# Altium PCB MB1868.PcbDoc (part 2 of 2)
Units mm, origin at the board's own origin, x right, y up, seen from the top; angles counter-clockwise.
Board outline 59.55 x 30 mm, 2 copper layers (Top Layer, Bottom Layer), stack 1.499 mm thick; 74 components, 54 nets, 296 pads, 554 vias.

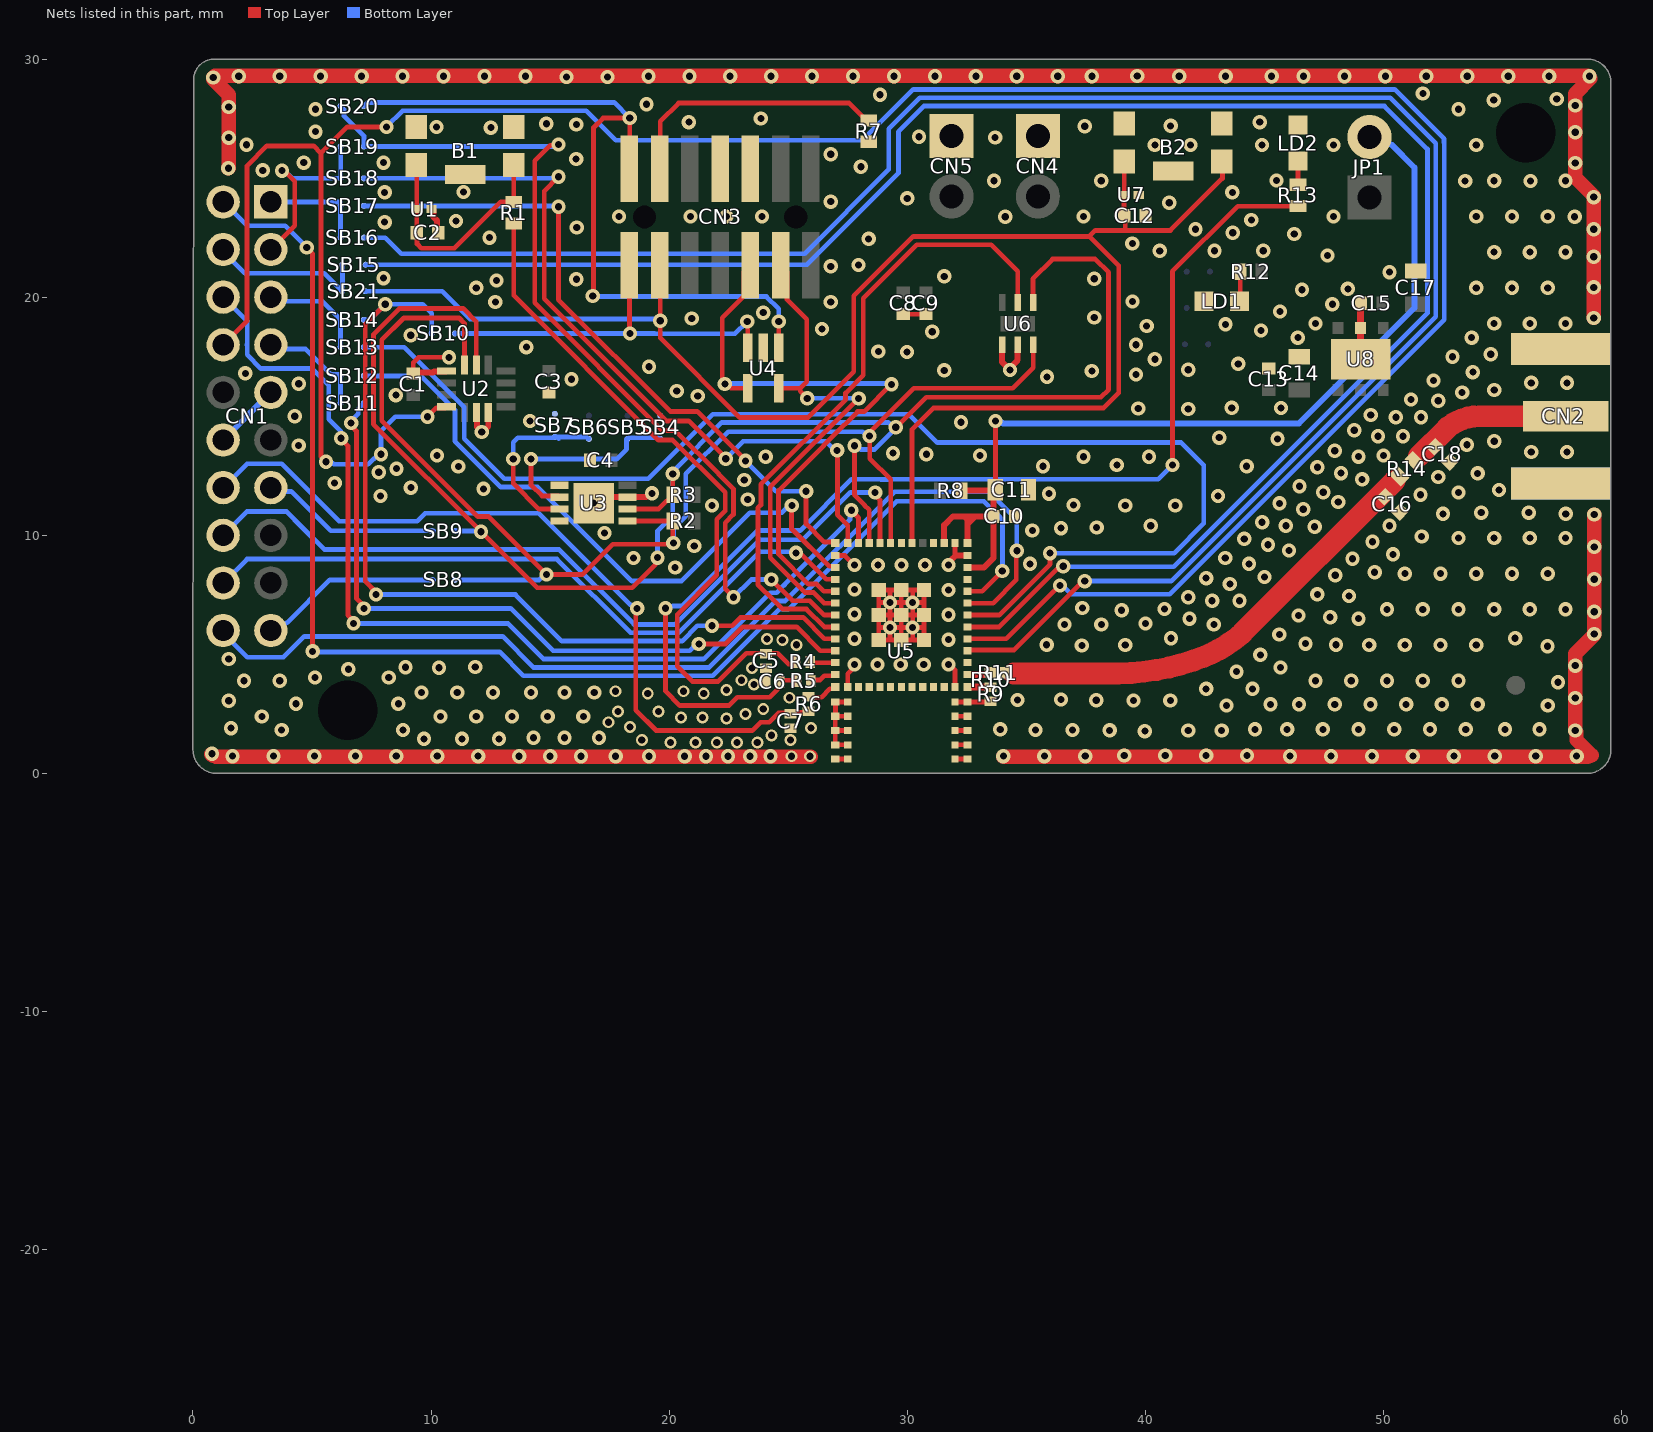
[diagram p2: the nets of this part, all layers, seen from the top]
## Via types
v1: diameter 0.6, hole 0.3, Top Layer to Bottom Layer, tented both sides, 522 vias
v2: diameter 0.5, hole 0.3, Top Layer to Bottom Layer, tented both sides, 32 vias

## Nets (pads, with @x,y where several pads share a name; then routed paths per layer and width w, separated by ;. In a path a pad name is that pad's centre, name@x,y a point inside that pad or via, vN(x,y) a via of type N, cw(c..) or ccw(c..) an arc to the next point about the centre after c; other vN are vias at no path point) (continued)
GND: B1.2 B1.4 B1.5 B2.2 B2.4 B2.5 C1.1 C2.1 C3.1 C4.1 C5.1 C6.1 C7.1 C8.1 C9.1 C10.1 C11.1 C12.1 C13.1 C14.1 C15.1 C16.2 C17.1 C18.2 CN1.5 CN1.16 CN2.2 CN2.3 CN2.4 CN2.5 CN3.5 CN3.7 CN4.1 CN5.1 LD1.2 LD2.2 R7.1 R9.2 SB4.1 SB7.2 U1.2 U2.1 U2.6 U2.7 U3.1 U3.4 U3.7 U3.EP U4.2 U5.1 U5.2 U5.3 U5.4 U5.5 U5.8 U5.15 U5.17 U5.19 U5.21 U5.24 U5.31 U5.43 U5.44 U5.45 U5.46 U5.47 U5.48 U5.49 U5.50 U5.51 U5.52 U5.53 U5.54 U5.55 U5.56 U5.57 U5.58 U5.59 U5.60 U5.61 U5.62 U5.63 U5.64 U5.65 U5.66 U5.67 U5.68 U5.69 U5.70 U5.71 U5.72 U5.73 U5.74 U5.75 U5.76 U5.77 U6.4 U6.5 U7.2 U8.2 U8.EP | length 182.7
  Top Layer w0.2: CN1.16@1.27,13.814 CN1.16@1.27,14 ; C1.1@9.255,16.845 9.255,17.255 9.473,17.473 v1(10.752,17.473) ; v1@19.192,11.76 v1(19.273,11.76) ; U5.46@26.964,1.199 U5.49@27.489,1.199 ; U5.46@26.975,1.2 U5.45@26.975,1.8 ; U5.44@26.975,2.4 26.975,1.814 26.989,1.799 U5.50@27.514,1.799 ; U5.43@26.975,3 26.989,2.986 26.989,2.399 U5.51@27.514,2.399 ; U5.31@26.975,9.15 27.382,9.15 v1(27.782,8.75) ; U5.43@26.981,2.995 U5.52@27.506,2.995 ; U5.47@26.989,0.599 U5.48@27.514,0.599 ; U5.53@27.498,3.631 27.498,4.183 27.782,4.467 v1(27.782,4.575) ; 28.8,6.125 v1@29.275,6.125 ; 28.8,7.175 v1@29.275,7.175 ; 29.275,5.6 v1@29.275,6.125 ; 29.275,7.7 v1@29.275,7.175 ; C8.1@29.834,19.287 C9.1@30.784,19.287 ; 30.225,5.6 v1@30.225,6.125 ; 30.225,7.7 v1@30.225,7.175 ; 30.7,6.125 v1@30.225,6.125 ; 30.7,7.175 v1@30.225,7.175 ; v1(31.726,4.575) 31.783,4.575 32.001,4.357 U5.63@32.001,3.614 ; U5.68@31.989,0.599 U5.1@32.514,0.599 ; U5.67@31.989,1.199 U5.2@32.514,1.199 ; U5.65@31.989,2.399 U5.4@32.514,2.399 ; 32,9.125 32,9.25 ; U5.19@32,9.675 32,9.25 ; U5.66@32.014,1.799 U5.3@32.539,1.799 ; U5.64@32.014,2.999 R9.2@33.3,2.999 ; 32.1,9.15 32,9.25 ; C15.1@49.034,19.722 C15.1@49.059,19.747 ; U5.76@28.8,6.65 U5.77@28.8,7.7 U5.72@29.75,7.7 ; U5.76@28.8,6.65 U5.73@29.75,6.65 ; U5.76@28.8,6.65 U5.75@28.8,5.6 U5.74@29.75,5.6 ; v1@29.275,6.125 v1@30.225,6.125 ; v1@29.275,6.125 v1@29.275,7.175 ; v1@29.275,7.175 v1@30.225,7.175 ; U5.74@29.75,5.6 U5.69@30.7,5.6 U5.70@30.7,6.65 ; U5.74@29.75,5.6 U5.73@29.75,6.65 ; U5.73@29.75,6.65 U5.70@30.7,6.65 ; U5.73@29.75,6.65 U5.72@29.75,7.7 ; U5.72@29.75,7.7 U5.71@30.7,7.7 U5.70@30.7,6.65 ; v1@30.225,6.125 v1@30.225,7.175
  Top Layer w0.25: C1.1@9.255,16.845 10.085,16.845 10.115,16.875 10.252,16.875 10.625,16.875 U2.1@10.65,16.9 ; U1.2@10.025,23.7 10.058,23.7 10.098,23.66 10.098,23.365 10.254,23.209 10.254,22.746 C2.1@10.3,22.7 ; U2.6@11.9,15.15 11.925,15.125 11.925,14.545 v1(12.129,14.341) 12.172,14.341 12.4,14.57 U2.7@12.4,15.15 ; v1(16.825,11.35) 17.075,11.6 U3.7@18.25,11.6 19.032,11.6 v1@19.192,11.76 ; v1@31.875,9 32,9.125 ; 32.1,9.15 U5.17@32.525,9.15 ; U6.4@33.984,17.662 33.984,17.272 34.311,16.945 v1(34.311,16.94) 34.311,17.035 34.634,17.358 U6.5@34.634,17.712
  Top Layer w0.3: U8.EP@49.034,17.547 U8.2@49.034,18.697 C15.1@49.034,19.722
  Top Layer w0.6: v1@0.767,0.809 0.809,0.767 0.858,0.734 0.912,0.712 0.97,0.7 1.659,0.7 10.258,0.7 v1@15,0.7 ; v1(1.486,25.411) 1.5,25.425 v1(1.5,26.7) v1(1.5,27.989) 1.5,28.5 0.85,29.15 v1(0.85,29.225) 0.925,29.3 1.899,29.3 v1(1.924,29.275) 1.949,29.3 3.619,29.3 v1(3.644,29.275) 3.669,29.3 5.338,29.3 v1(5.363,29.275) 5.388,29.3 7.058,29.3 v1(7.083,29.275) 7.108,29.3 8.778,29.3 v1(8.803,29.275) 8.828,29.3 10.497,29.3 v1(10.523,29.275) 10.548,29.3 12.217,29.3 v1(12.242,29.275) 12.267,29.3 13.937,29.3 v1(13.962,29.275) 13.987,29.3 15.641,29.3 v1(15.691,29.25) 15.741,29.3 17.361,29.3 v1(17.411,29.25) 17.461,29.3 19.08,29.3 19.13,29.25 19.18,29.3 20.8,29.3 v1@20.85,29.25 ; v1@15.05,0.7 v1@16.2,0.7 ; v1@16.4,0.7 v1@17.7,0.7 ; v1@17.8,0.7 v1@21.542,0.7 ; v1(20.85,29.275) 20.875,29.3 22.536,29.3 v1(22.561,29.275) 22.586,29.3 24.255,29.3 v1(24.28,29.275) 24.305,29.3 25.975,29.3 v1(26,29.275) 26.025,29.3 27.695,29.3 v1(27.72,29.275) 27.745,29.3 29.414,29.3 v1(29.439,29.275) ; v1@21.774,0.7 22.469,0.7 23.4,0.7 24.25,0.7 v2@25.95,0.7 ; v1@29.435,29.3 29.439,29.3 29.764,29.3 v1@34.599,29.3 ; v1@34.034,0.7 v1@37.474,0.7 ; v1(34.599,29.275) 34.624,29.3 36.293,29.3 v1(36.318,29.275) 36.343,29.3 37.725,29.3 v1(37.75,29.275) 37.775,29.3 39.643,29.3 v1(39.655,29.288) 39.666,29.3 41.401,29.3 v1(41.421,29.28) 41.441,29.3 43.333,29.3 43.369,29.264 43.406,29.3 45.275,29.3 v1@45.3,29.275 ; v1(37.474,0.725) 37.499,0.7 39.061,0.7 v1(39.111,0.75) 39.161,0.7 40.78,0.7 v1(40.83,0.75) 40.88,0.7 42.5,0.7 v1(42.55,0.75) 42.6,0.7 44.22,0.7 v1(44.27,0.75) 44.32,0.7 46.072,0.7 v1@51.231,0.7 ; v1@45.289,29.264 45.325,29.3 46.612,29.3 46.637,29.275 46.662,29.3 48.331,29.3 v1(48.356,29.275) 48.381,29.3 50.051,29.3 v1(50.076,29.275) 50.101,29.3 51.771,29.3 v1(51.796,29.275) 51.821,29.3 53.491,29.3 v1(53.516,29.275) 53.541,29.3 55.21,29.3 v1(55.235,29.275) 55.26,29.3 56.93,29.3 v1(56.955,29.275) 56.98,29.3 58.58,29.3 58.636,29.289 v1(58.65,29.275) ; v1(51.231,0.725) 51.256,0.7 52.926,0.7 v1(52.951,0.725) ; v1@52.951,0.7 58.58,0.7 58.638,0.712 58.692,0.734 58.741,0.767 ; 58.692,0.814 58.1,1.406 58.1,1.738 58.036,1.803 58.05,1.817 v1(58.05,3.164) v1(58.05,4.525) 58.05,5.025 58.85,5.825 v1(58.85,10.874) ; v1@58.692,29.186 58.05,28.544 v1(58.05,28.049) v1(58.05,26.925) v1(58.05,25.636) 58.05,25.026 58.825,24.251 v1(58.825,24.2) v1(58.825,22.85) v1(58.825,21.7) v1(58.825,20.411) 58.825,19.132 v1@58.836,19.122
  Bottom Layer w0.25: CN1.16@1.27,14 CN1.5@3.27,16
  other v1: 1.659,0.725 3.379,0.725 5.099,0.725 6.819,0.725 8.538,0.725 10.258,0.725 11.978,0.725 13.698,0.722 15,0.722 16.3,0.722 17.75,0.722 19.15,0.722 20.65,0.722 21.542,0.722 22.469,0.722 23.4,0.722 24.25,0.722 34.034,0.725 35.754,0.725 46.072,0.725 47.792,0.725 49.512,0.725 54.671,0.725 56.39,0.725 58.11,0.725 0.8,0.825 9.7,1.45 11.3,1.45 12.85,1.45 14.3,1.5 15.6,1.5 17.05,1.5 39.975,1.775 38.495,1.808 41.8,1.8 43.2,1.8 58.05,1.803 3.725,1.825 8.825,1.825 35.385,1.825 36.935,1.825 33.9,1.85 44.6,1.85 45.95,1.85 47.45,1.85 48.95,1.85 50.45,1.85 51.95,1.85 53.45,1.85 55.1,1.85 56.55,1.85 1.6,1.9 2.895,2.39 10.395,2.39 11.895,2.39 13.395,2.39 14.895,2.39 16.395,2.39 43.4,2.85 56.9,2.85 45.25,2.9 46.45,2.9 47.95,2.9 49.45,2.9 50.95,2.9 52.45,2.9 53.95,2.9 4.325,2.925 8.625,2.925 1.5,3.05 39.495,3.058 41.045,3.058 34.631,3.083 37.935,3.075 36.456,3.108 9.6,3.4 11.1,3.4 12.6,3.4 14.2,3.4 15.6,3.4 16.85,3.4 42.55,3.55 44.5,3.55 57.325,3.825 2.145,3.89 3.645,3.89 47.145,3.89 48.645,3.89 50.145,3.89 51.645,3.89 53.145,3.89 5.125,4.025 8.225,4.025 43.826,4.274 6.525,4.375 8.926,4.456 10.337,4.437 45.676,4.449 11.856,4.472 28.75,4.575 29.719,4.575 30.688,4.575 1.5,4.8 44.826,4.979 56.881,5.342 37.33,5.367 35.85,5.4 39.155,5.392 48,5.4 49.395,5.39 50.895,5.39 52.395,5.39 53.895,5.39 46.726,5.449 31.726,5.619 27.782,5.656 41.075,5.675 55.525,5.675 45.626,5.829 58.85,5.85 29.269,6.127 30.219,6.127 36.6,6.25 38.15,6.25 42.875,6.25 40.005,6.292 41.85,6.5 48.95,6.5 47.757,6.559 46.426,6.629 31.726,6.662 27.782,6.687 58.85,6.791 39,6.85 40.8,6.9 50.145,6.89 51.645,6.89 53.145,6.89 54.645,6.89 56.145,6.89 57.645,6.89 37.35,6.95 29.269,7.177 30.219,7.177 42.8,7.25 43.95,7.25 41.8,7.4 48.55,7.45 47.219,7.52 31.726,7.706 27.782,7.719 43.546,7.951 58.85,8.152 42.55,8.2 45,8.25 47.969,8.32 50.895,8.39 52.395,8.39 53.895,8.39 55.395,8.39 56.895,8.39 49.625,8.45 20.25,8.65 28.768,8.75 29.754,8.75 30.74,8.75 31.726,8.75 35.15,8.8 44.346,8.801 48.698,9.012 18.5,9.05 43.35,9.05 50.4,9.2 46.03,9.36 58.85,9.513 21.05,9.55 45.146,9.601 49.539,9.728 44.15,9.85 53.145,9.89 54.645,9.89 56.145,9.89 57.645,9.89 51.6,9.95 17.279,10.1 35.25,10.2 36.45,10.3 37.95,10.325 47.105,10.36 40.225,10.4 45.896,10.401 50.25,10.4 44.9,10.55 52.5,10.9 57.65,10.9 54.1,10.95 56.1,10.95 46.626,11.093 21.8,11.25 39.15,11.25 41.25,11.25 36.975,11.275 45.63,11.342 48.1,11.4 23.3,11.5 7.872,11.651 43.05,11.65 51.55,11.7 35.95,11.75 53.15,11.8 47.466,11.809 54.85,11.9 12.2,11.95 9.15,12 46.47,12.058 5.95,12.2 23.15,12.323 49.1,12.35 52.3,12.45 48.216,12.609 53.95,12.6 7.8,12.65 8.55,12.8 47.22,12.858 11.145,12.89 35.7,12.9 44.25,12.9 38.8,12.95 24.05,13.3 37.4,13.3 40.15,13.3 48.946,13.301 10.25,13.35 33.05,13.35 50,13.35 30.8,13.4 29.4,13.45 56.2,13.5 57.7,13.5 47.95,13.55 4.439,13.771 53.5,13.8 54.65,13.95 45.55,14.05 43.1,14.1 49.766,14.159 50.82,14.158 48.77,14.408 32.251,14.745 14.15,14.8 50.516,14.959 51.57,14.958 4.275,15 49.461,15.055 41.8,15.3 39.7,15.325 43.625,15.35 45.691,15.342 52.3,15.65 51.15,15.7 21.2,15.85 8.52,15.885 53.3,16 20.316,16.055 54.65,16.1 4.445,16.363 56.2,16.4 57.7,16.4 52.1,16.5 15.9,16.55 35.87,16.654 39.6,16.75 2.2,16.8 53.75,16.85 37.75,16.9 31.55,16.925 41.8,16.95 19.15,17.075 43.9,17.2 40.395,17.39 52.9,17.5 54.5,17.6 28.783,17.716 29.988,17.695 14,17.9 39.6,18 46.4,18.3 53.7,18.3 9.146,18.401 31.05,18.55 44.85,18.6 26.42,18.661 40.052,18.791 43.361,18.858 47.145,18.89 54.645,18.89 56.145,18.89 57.645,18.89 20.95,19.1 58.825,19.122 37.85,19.15 23.95,19.35 45.65,19.4 47.85,19.7 12.7,19.8 26.785,19.793 39.453,19.821 46.572,20.314 48.5,20.35 11.895,20.39 53.895,20.39 55.395,20.39 56.895,20.39 12.75,20.7 16.1,20.75 37.85,20.775 8,20.8 31.55,20.875 50.25,21.05 26.785,21.294 27.95,21.35 47.65,21.75 54.645,21.89 56.145,21.89 57.645,21.89 40.599,21.944 42.9,21.95 44.95,21.95 39.45,22.25 28.375,22.45 12.45,22.5 46.25,22.65 43.666,22.705 42.1,22.85 16.116,22.93 8.05,23.15 11.05,23.2 44.448,23.244 34.114,23.377 58.025,23.375 17.895,23.39 20.895,23.39 22.395,23.39 23.895,23.39 37.395,23.39 47.895,23.39 53.895,23.39 55.395,23.39 56.895,23.39 41,23.962 26.785,24.011 30,24.15 8.05,24.4 43.65,24.4 11.361,24.414 53.425,24.875 56.175,24.875 33.645,24.89 38.145,24.89 45.5,24.9 54.645,24.89 57.645,24.89 2.928,25.325 28.05,25.475 4.65,25.65 8,25.65 16.091,25.805 26.785,26.005 2.25,26.4 40.395,26.39 41.895,26.39 44.895,26.39 47.895,26.39 53.895,26.39 33.689,26.702 30.489,26.739 5.15,26.95 12.51,27.119 10.224,27.15 37.45,27.175 41.059,27.194 16.1,27.25 14.841,27.28 20.825,27.35 44.804,27.349 23.85,27.5 5.145,27.89 53.145,27.89 19.05,28.1 54.625,28.275 57.275,28.325 28.85,28.5 51.65,28.55 19.13,29.275 31.159,29.275 32.879,29.275 43.369,29.28 45.3,29.28 46.637,29.28
  other v2: 25.129,0.722 25.911,0.722 20.05,1.301 21.1,1.3 22,1.3 22.85,1.3 23.7,1.3 18.85,1.4 25.1,1.4 24.3,1.6 25.95,1.9 18.35,1.95 17.45,2.15 22.4,2.3 20.5,2.35 21.4,2.35 23.2,2.5 17.85,2.6 19.55,2.6 23.95,2.7 25.055,3.178 19.1,3.35 21.45,3.35 17.75,3.45 20.6,3.45 22.4,3.5 23.56,3.728 23.034,3.913 23.473,4.429 25.35,5.4 24.75,5.6 24.1,5.65
GNDDetect: CN3.11 R7.2 | length 10.4
  Top Layer w0.2: CN3.11@19.625,26.325 19.625,27.379 20.396,28.15 27.555,28.15 28.125,27.58 28.28,27.425 R7.2@28.375,27.425
I2C1_SCL: R3.2 SB9.1 U2.13 U3.6 U5.27 U6.1 | length 70.2
  Top Layer w0.2: U2.13@11.9,17.15 11.9,18.975 11.35,19.525 8.678,19.525 7.581,18.428 7.581,14.669 v1(12.1,10.15) 14.45,7.8 18.45,7.8 19.436,8.786 19.436,8.983 v1(19.512,9.06) ; U3.6@18.25,11.1 19.55,11.1 19.9,11.45 19.995,11.45 20.15,11.605 R3.2@20.15,11.7 v1(20.15,12.58) v1@20.15,12.68 ; v1(27.779,13.759) 27.779,11.698 28.2,11.278 28.2,11.271 28.4,11.071 U5.27@28.4,9.675 ; v1@29.5,14.5 30.8,15.8 38.133,15.8 38.45,16.117 38.45,21.038 37.888,21.6 36.1,21.6 35.274,20.774 U6.1@35.274,19.777
  Bottom Layer w0.2: SB9.1@11,10.175 11.05,10.175 12.075,10.175 v1(12.1,10.15) ; v1(19.512,9.06) 19.512,10.187 20.15,10.825 v1@20.15,12.537 ; v1@20.169,12.68 20.289,12.8 20.289,12.818 22.208,14.738 29.204,14.738 29.404,14.538 v1(29.513,14.538) ; v1(27.779,13.759) 27.888,13.759 28.047,13.6 28.617,13.6 v1@29.533,14.517
I2C1_SDA: R2.2 SB8.1 U2.14 U3.5 U5.25 U6.6 | length 56.8
  Top Layer w0.2: U2.14@11.4,17.15 11.4,18.909 11.184,19.125 8.85,19.125 7.931,18.206 7.931,14.814 11.957,10.787 12.413,10.787 v1(14.85,8.35) 16.351,8.35 17.626,9.625 19.969,9.625 20.044,9.7 v1@20.125,9.7 ; U3.5@18.25,10.6 R2.2@20.15,10.6 v1@20.15,9.7 ; v1@28.364,14.267 30.272,16.175 34.427,16.175 35.284,17.032 U6.6@35.284,17.997 ; v1@28.41,14.271 v1(28.41,14.171) 28.422,14.158 28.422,13.222 29.3,12.344 U5.25@29.3,9.675
  Bottom Layer w0.2: 11.225,8.125 14.533,8.125 14.758,8.35 v1(14.85,8.35) ; v1(20.175,9.675) 20.175,10.285 20.7,10.809 20.7,12.575 22.475,14.35 28.122,14.35 28.427,14.046 v1@28.472,14.046
NetB1_1: B1.1 B1.3 C2.2 R1.1 U1.1 | length 9.8
  Top Layer w0.2: B1.1@9.375,25.55 9.4,25.525 U1.1@9.4,23.7 C2.2@9.4,22.7 9.413,22.687 9.413,22.237 9.594,22.056 10.981,22.056 12.925,24 R1.1@13.475,24 B1.3@13.475,25.55
NetC6_1: C18.1 CN2.1 R14.2 | length 6.8
  Top Layer w0.914: 51.483,13.317 52.688,14.523 cw(c54.043,12.838) 54.016,15 54.022,15 56.3,15 CN2.1@57.65,15
NetC7_1: C16.1 R11.1 R14.1 | length 19
  Top Layer w0.914: 34.475,4.2 38.849,4.2 38.853,4.2 ccw(c38.756,14.276) 42.024,4.744 ccw(c40.331,10.156) 44.051,5.877 50.462,12.288
NetCN1_1: CN1.1 SB16.2 SB17.2 | length 4.3
  Bottom Layer w0.2: CN1.1@3.275,24.005 CN1.1@3.27,24 6.2,24 ; SB16.2@6.2,22.5 SB17.2@6.2,23.833
NetCN1_2: CN1.2 SB18.2 SB19.2 | length 7.9
  Top Layer w0.2: CN1.2@3.27,22 4.275,23.005 4.275,24.864 3.825,25.314 v1(3.735,25.314)
  Bottom Layer w0.2: v1(3.735,25.314) 3.843,25.314 4.165,24.992 6.206,24.992 SB19.2@6.206,26.325
NetCN1_3: CN1.3 SB13.2 SB14.2 | length 4.5
  Bottom Layer w0.2: CN1.3@3.27,20 3.445,19.825 5.425,19.825 SB14.2@6.2,19.05 SB13.2@6.2,17.9
NetCN1_4: CN1.4 SB11.2 SB12.2 | length 4.6
  Bottom Layer w0.2: CN1.4@3.27,18 3.45,17.82 4.73,17.82 5.8,16.75 6.17,16.75 SB12.2@6.22,16.7 ; SB11.2@6.2,15.55 SB12.2@6.2,16.7
NetCN1_7: CN1.7 SB9.2 | length 7.6
  Bottom Layer w0.2: CN1.7@3.27,12 3.427,11.843 4.127,11.843 5.783,10.188 SB9.2@10.112,10.188
NetCN1_10: CN1.10 SB8.2 | length 7.7
  Bottom Layer w0.2: CN1.10@3.27,6 3.595,6 3.924,6.33 3.955,6.33 5.75,8.125 10.045,8.125 SB8.2@10.1,8.125
NetCN1_12: CN1.12 SB15.1 SB21.1 | length 6.9
  Bottom Layer w0.2: CN1.12@1.27,22 1.27,21.905 2.175,21 2.856,21 5.504,21 SB21.1@6.265,20.239 ; SB21.1@6.275,20.229 SB21.1@6.265,20.239 ; SB15.1@6.275,21.362 6.275,20.25 SB21.1@6.265,20.239
NetLD1_1: LD2.1 R13.2 | length 1
  Top Layer w0.2: R13.2@46.406,24.722 46.409,24.725 LD2.1@46.409,25.722
NetLD2_1: LD1.1 R12.2 | length 1.3
  Top Layer w0.2: LD1.1@43.959,19.828 43.98,19.849 R12.2@43.98,21.072
NetR1_1: R9.1 R10.2 U5.6 | length 0.8
  Top Layer w0.3: U5.6@32.525,3.625 R9.1@33.325,3.625
NetR2_1: R10.1 R11.2 U5.7 | length 1
  Top Layer w0.3: U5.7@32.55,4.15 R11.2@33.5,4.15
NetSB13_2: SB4.2 SB5.2 U3.2 | length 8.6
  Top Layer w0.2: v1(14.2,13.2) 14.2,12.111 14.661,11.65 15.35,11.65 U3.2@15.4,11.6
  Bottom Layer w0.2: v1(14.2,13.2) 17.8,13.2 18.212,13.612 18.212,14.032 SB5.2@18.25,14.07 ; SB5.2@18.265,14.05 18.315,14.1 19.55,14.1 19.6,14.05 SB4.2@19.625,14.05
NetSB15_2: SB6.2 SB7.1 U3.3 | length 7.5
  Top Layer w0.2: v1(13.45,13.2) 13.45,12.175 14.525,11.1 U3.3@15.4,11.1
  Bottom Layer w0.2: v1(13.45,13.2) 13.45,13.9 13.65,14.1 15.137,14.1 15.151,14.115 15.19,14.115 SB7.1@15.2,14.125 SB7.1@15.285,14.125 ; 15.36,14.05 SB7.1@15.285,14.125 ; SB6.2@16.625,14.05 16.61,14.05 16.535,14.125 SB7.1@15.285,14.125
NRST: B2.1 B2.3 C12.2 CN3.12 SB21.2 U5.23 U7.1 | length 71.9
  Top Layer w0.2: CN3.12@19.6,21.336 19.624,21.312 v1(19.624,19.012) 19.624,18.289 22.972,14.941 25.827,14.941 27.75,16.864 27.75,20.05 30.25,22.55 37.65,22.55 ; U5.23@30.2,9.675 30.2,14.45 31.1,15.35 38.249,15.35 38.875,15.976 38.875,21.325 37.65,22.55 ; C12.2@39.097,23.418 U7.1@39.097,24.293 ; C12.2@39.109,23.418 39.15,23.378 39.15,22.804 ; U7.1@39.109,24.431 B2.1@39.109,25.697 B2.1@39.109,25.856 ; B2.3@43.234,25.831 43.234,24.984 41.05,22.8 37.9,22.8 37.65,22.55
  Bottom Layer w0.2: SB21.2@7.25,20.25 7.261,20.239 7.275,20.239 7.286,20.25 10.466,20.25 11.629,19.087 v1@19.624,19.087
PA0: U5.37 U6.2 | length 27
  Top Layer w0.2: U5.37@26.975,6.15 26.515,6.15 25.765,6.9 24.767,6.9 24.076,7.591 24.063,7.591 23.724,7.931 23.724,11.146 23.85,11.272 23.85,12.137 27.407,15.695 27.407,15.974 28.15,16.717 28.15,19.955 30.395,22.2 33.525,22.2 34.634,21.091 U6.2@34.634,19.777
PA1: SB15.2 U5.11 | length 80.8
  Top Layer w0.2: U5.11@32.525,6.15 33.855,6.15 v1@36.395,8.69 ; v1@36.473,8.623 v1(36.55,8.7)
  Bottom Layer w0.2: SB15.2@7.25,21.362 25.787,21.362 29.625,25.2 29.625,26.95 30.7,28.025 50.035,28.025 51.842,26.217 51.842,19.332 41.185,8.675 36.575,8.675 v1(36.55,8.7)
PA2: CN1.20 U5.13 | length 43.3
  Top Layer w0.2: U5.13@32.525,7.15 33.6,7.15 34.575,8.125 34.575,9.083 34.593,9.1 v1@34.593,9.332
  Bottom Layer w0.2: CN1.20@1.27,6 1.27,5.88 2.275,4.875 3.8,4.875 4.675,5.75 5.722,5.75 13,5.75 14.3,4.45 21.678,4.45 24.469,7.241 24.871,7.241 29.405,11.775 29.409,11.775 29.459,11.825 33.43,11.825 34.6,10.655 v1@34.6,9.375
  other v1: 34.6,9.35
PA3: CN1.13 U5.28 | length 43.1
  Top Layer w0.2: v1(6.223,14.077) 6.223,14.046 6.51,13.759 6.51,6.641 6.742,6.408 v1(6.742,6.3) ; v1(27.65,11.05) 27.65,11.033 27.95,10.733 U5.28@27.95,9.675 U5.28@27.93,9.695
  Bottom Layer w0.2: CN1.13@1.27,20 2.216,19.054 2.275,18.995 2.275,18.1 ccw(c3.27,18) 2.275,17.9 2.275,17.581 2.856,17 5,17 5.7,16.3 5.7,14.872 6.223,14.349 v1(6.223,14.077) ; v1(6.742,6.3) 13.225,6.3 14.725,4.8 21.45,4.8 24.241,7.591 24.519,7.591 24.841,7.914 27.59,10.662 27.59,10.99 v1(27.65,11.05)
PA4: SB16.1 U5.9 | length 82.5
  Top Layer w0.2: U5.9@32.525,5.15 32.56,5.185 34.481,5.185 36.636,7.34 36.638,7.34 36.96,7.662 36.96,7.664 37.371,8.075 v1(37.451,8.075)
  Bottom Layer w0.2: SB16.1@7.225,22.5 8.075,22.5 8.747,21.828 25.687,21.828 29.225,25.366 29.225,27.075 30.525,28.375 50.275,28.375 52.192,26.458 52.192,19.187 41.08,8.075 v1(37.451,8.075)
PA5: SB11.1 U5.39 | length 30.4
  Top Layer w0.2: v1(6.643,14.714) 6.643,14.606 6.781,14.467 6.781,14.46 6.864,14.378 6.864,7.348 7.177,7.034 v1(7.177,6.926) ; v1(21.246,5.435) 22.377,5.435 23.092,6.15 25.35,6.15 26.35,5.15 U5.39@26.975,5.15
  Bottom Layer w0.2: v1(6.643,14.714) 6.643,14.802 6.937,15.096 6.937,15.298 7.175,15.535 SB11.1@7.175,15.55 ; v1(7.177,6.926) 13.349,6.926 15.125,5.15 20.853,5.15 21.138,5.435 v1(21.246,5.435)
PA6: SB13.1 U5.12 | length 54.6
  Top Layer w0.2: U5.12@32.525,6.65 33.86,6.65 35.993,8.783 v1(35.993,9.25)
  Bottom Layer w0.2: SB13.1@7.175,17.9 8.869,17.9 11.389,15.38 11.389,14.061 13.075,12.375 19.111,12.375 19.917,13.181 19.922,13.181 21.828,15.088 30.062,15.088 31.255,13.895 32.817,13.895 32.822,13.9 33.278,13.9 33.283,13.895 41.505,13.895 42.45,12.95 42.45,10.5 41.2,9.25 v1(35.993,9.25)
PA7: SB18.1 U5.29 | length 33.2
  Top Layer w0.2: v1(15.35,25.056) 14.75,24.456 14.75,19.931 19.881,14.8 20.825,14.8 22.375,13.25 v1(22.375,13.215) ; v1@27.064,13.556 27.064,10.858 27.5,10.422 U5.29@27.5,9.675
  Bottom Layer w0.2: SB18.1@7.175,24.992 7.225,24.992 15.206,24.992 15.269,25.056 v1(15.35,25.056) ; v1(22.375,13.215) 23.104,13.944 26.58,13.944 26.957,13.568 v1(27.053,13.568)
PA8: CN1.14 U2.4 U5.10 | length 114.9
  Top Layer w0.2: CN1.14@1.27,18 2.27,19 2.27,25.52 3.1,26.35 5.075,26.35 5.375,26.05 ; v1(5.591,13.087) 5.375,13.303 5.375,26.05 ; v1(8.125,27.15) 6.475,27.15 5.375,26.05 ; v1(9.85,14.975) 10.225,15.35 10.6,15.35 U2.4@10.65,15.4 ; U5.10@32.525,5.65 34.15,5.65 36.39,7.89 v1(36.41,7.89)
  Bottom Layer w0.2: v1(5.591,13.087) 5.667,13.011 5.877,13.011 5.908,12.98 7.352,12.98 7.572,13.2 7.592,13.2 7.792,13.4 v1(7.9,13.4) 7.9,14.381 8.494,14.975 v1(9.85,14.975) ; v1(8.125,27.15) 8.805,27.83 16.515,27.83 17.76,26.585 28.11,26.585 30.25,28.725 50.47,28.725 52.542,26.653 52.542,26.487 52.55,26.479 52.55,19.05 41.025,7.525 36.883,7.525 36.518,7.89 v1(36.41,7.89)
PA9-TX: SB10.2 SB14.1 U5.38 | length 37.7
  Top Layer w0.2: v1(7.684,7.51) 7.684,7.618 7.231,8.072 7.231,18.856 v1(8.075,19.7) ; v1(21.8,6.2) 22.647,6.2 22.997,6.55 25.62,6.55 26.52,5.65 U5.38@26.975,5.65
  Bottom Layer w0.2: SB14.1@7.175,19.05 7.425,19.05 v1(8.075,19.7) 9.65,19.7 10.025,19.325 SB10.2@10.025,18.475 ; v1(7.684,7.51) 13.54,7.51 15.494,5.556 20.539,5.556 21.183,6.2 v1(21.8,6.2)
PA10-RX: SB19.1 SB20.2 U5.36 | length 39
  Top Layer w0.2: v1(15.35,26.413) 15.317,26.38 15.005,26.38 14.35,25.725 14.35,19.766 19.716,14.4 20.25,14.4 22.095,12.555 22.095,12.55 22.7,11.945 22.7,10.877 22.35,10.527 22.35,7.75 v1(22.7,7.4) ; v1(24.291,8.141) 25.168,7.265 25.168,7.25 25.91,7.25 26.51,6.65 U5.36@26.975,6.65
  Bottom Layer w0.2: SB20.2@6.2,28.023 6.338,27.885 6.338,27.612 7.181,26.769 7.181,26.331 SB19.1@7.175,26.325 ; SB19.1@7.181,26.325 v1@15.181,26.325 ; v1(22.7,7.4) 23.441,8.141 v1(24.291,8.141)
PA11: SB12.1 U5.32 | length 27.1
  Top Layer w0.2: v1(25.15,11.25) 25.136,11.236 25.136,10.281 26.717,8.7 26.925,8.7 U5.32@26.975,8.65
  Bottom Layer w0.2: SB12.1@7.225,16.689 9.585,16.689 11,15.274 11,13.955 12.93,12.025 14.475,12.025 18.425,8.075 20.512,8.075 23.387,10.95 24.732,10.95 24.867,11.085 24.877,11.085 25.042,11.25 v1(25.15,11.25)
PA12: SB17.1 U5.30 | length 28.8
  Top Layer w0.2: v1(15.35,23.8) 15.35,19.897 20.047,15.2 21.175,15.2 23.2,13.175 v1(23.2,13.125) ; v1(25.75,11.85) 25.75,10.478 26.514,9.714 26.936,9.714 U5.30@26.975,9.675
  Bottom Layer w0.2: SB17.1@7.175,23.833 15.317,23.833 v1(15.35,23.8) ; v1(23.2,13.125) 24.475,11.85 v1(25.75,11.85)
PA13-SWDIO: CN3.4 U4.5 U5.35 | length 21.6
  Top Layer w0.2: CN3.4@24.68,21.336 24.95,21.066 24.95,19.9 25.775,19.075 25.775,16.45 25.5,16.175 ; U4.5@24.7,15.675 24.7,16.075 U4.5@24.6,16.175 25.5,16.175 ; v1(25.8,15.75) 25.5,16.05 25.5,16.175 ; U5.35@26.975,7.15 26.9,7.15 26.505,7.15 26.055,7.6 25.7,7.6 24.243,9.057 24.243,12.032 v1(27.957,15.746)
  Bottom Layer w0.2: v1(25.8,15.75) 27.954,15.75 v1(27.957,15.746)
PA14-SWCLK: CN3.6 U4.4 U5.34 | length 25.9
  Top Layer w0.2: v1@22.317,16.333 22.225,16.425 22.225,19.126 23.14,20.041 23.14,21.066 CN3.6@23.41,21.336 ; v1(22.337,16.353) 22.418,16.353 22.597,16.175 U4.4@23.3,16.175 ; U5.34@26.975,7.65 26.5,7.65 26.2,7.95 25.85,7.95 24.593,9.207 24.593,11.876 26.503,13.786 26.503,13.796 26.825,14.118 26.835,14.118 27.913,15.196 28.185,15.196 29.328,16.339 v1(29.339,16.339)
  Bottom Layer w0.2: v1@22.337,16.375 29.303,16.375 v1(29.339,16.339)
PB0: C6.2 R5.1 R13.1 | length 48.1
  Top Layer w0.2: v1(19.848,6.938) 19.848,3.446 20.443,2.85 22.508,2.85 22.858,3.2 24.215,3.2 24.55,3.535 24.55,3.739 C6.2@24.65,3.839 24.728,3.916 R5.1@25.366,3.916 ; v1(41.134,12.947) 41.134,21.084 43.872,23.822 R13.1@46.406,23.822
  Bottom Layer w0.2: v1(19.848,6.938) 19.924,7.015 20.151,7.015 20.165,7.029 20.527,7.029 23.698,10.2 25.505,10.2 27.655,12.35 28.878,12.35 28.884,12.344 29.3,12.344 29.306,12.35 40.537,12.35 v1(41.134,12.947)
PB0_S: R5.2 U5.41 | length 1.1
  Top Layer w0.2: R5.2@25.947,3.887 25.979,3.92 26.329,3.92 26.51,4.1 26.925,4.1 U5.41@26.975,4.15
PB1: C5.2 R1.2 R4.1 | length 29.4
  Top Layer w0.2: R1.2@13.475,23.1 13.475,20.075 19.55,14 20.15,14 22.35,11.8 22.35,11.022 22,10.672 22,8.332 20.34,6.672 20.34,4.498 20.979,3.858 22.045,3.858 23.237,5.05 23.85,5.05 24.55,5.05 25.013,4.587 R4.1@25.313,4.587
PB1_S: R4.2 U5.40 | length 1.1
  Top Layer w0.2: R4.2@25.916,4.686 25.951,4.65 U5.40@26.975,4.65
PB2: C7.2 CN1.17 R6.1 | length 32.8
  Top Layer w0.2: v1(18.654,6.93) 18.6,6.875 18.6,2.65 19.449,1.801 21.344,1.801 21.346,1.8 23.485,1.8 23.835,2.15 24.196,2.15 24.596,2.55 C7.2@25.05,2.55 ; C7.2@25.059,2.559 25.798,2.559 R6.1@25.853,2.614
  Bottom Layer w0.2: CN1.17@1.27,12 2.27,13 3.725,13 6.138,10.588 9.409,10.588 9.747,10.925 14.514,10.925 18.357,7.081 18.395,7.081 18.546,6.93 v1(18.654,6.93)
PB2_S: R6.2 U5.42 | length 1.2
  Top Layer w0.2: R6.2@25.95,3.2 26.4,3.2 26.75,3.55 26.9,3.55 U5.42@26.975,3.625
PB4: CN1.19 U5.33 | length 29.3
  Top Layer w0.2: v1(25.321,9.263) 25.398,9.186 25.569,9.186 26.605,8.15 U5.33@26.975,8.15
  Bottom Layer w0.2: CN1.19@1.27,8 2.27,9 15.284,9 18.378,5.906 20.394,5.906 23.796,9.308 25.276,9.308 v1(25.321,9.263)
PB5: CN1.18 U5.26 | length 34.3
  Top Layer w0.2: v1(28.65,11.8) 28.65,11.692 28.85,11.492 28.85,9.75 U5.26@28.85,9.675
  Bottom Layer w0.2: CN1.18@1.27,10 2.27,11 3.925,11 4.6,10.325 5.525,9.4 15.379,9.4 18.523,6.256 20.249,6.256 23.809,9.816 25.616,9.816 27.6,11.8 v1(28.65,11.8)
PB8: CN1.11 U5.14 | length 58.1
  Top Layer w0.2: v1(4.777,22.089) 4.777,22.07 5.025,21.822 v1(5.025,5.125) ; U5.14@32.525,7.65 33.14,7.65 v1(33.987,8.497)
  Bottom Layer w0.2: CN1.11@1.27,24 2.27,23 3.867,23 v1(4.777,22.089) ; v1(5.025,5.125) 5.05,5.1 12.875,5.1 13.875,4.1 21.823,4.1 21.948,4.225 24.614,6.891 25.016,6.891 29.55,11.425 33.218,11.425 34,10.643 34,8.51 v1(33.987,8.497)
VCP_RX: CN3.13 SB20.1 U4.1 | length 31.2
  Top Layer w0.2: v1(16.792,20.048) 16.825,20.081 16.825,27.125 17.22,27.52 v1(18.345,27.52) 18.341,27.516 CN3.13@18.341,26.339 ; CN3.13@18.316,25.514 CN3.13@18.33,25.5 ; U4.1@24.6,17.875 v1(24.6,18.975)
  Bottom Layer w0.2: SB20.1@7.175,28.023 7.332,28.18 17.686,28.18 v1(18.345,27.52) ; v1@16.792,19.948 v1@16.849,20.005 ; v1@16.792,20.025 24.083,20.025 24.6,19.508 v1(24.6,18.975)
VCP_TX: CN3.14 SB10.1 U4.3 | length 16.6
  Top Layer w0.2: CN3.14@18.33,21.336 18.33,18.403 v1@18.358,18.375 ; v1(23.275,18.975) 23.3,18.95 U4.3@23.3,17.875
  Bottom Layer w0.2: SB10.1@11,18.475 v1(18.358,18.475) 19.383,18.475 19.396,18.462 22.762,18.462 v1(23.275,18.975)
VDD: C10.2 C11.2 JP1.2 R8.1 U5.16 U5.18 U5.20 | length 41
  Top Layer w0.2: C11.2@33.69,11.915 33.7,11.925 v1(33.7,14.8)
  Top Layer w0.25: U5.20@31.55,9.675 31.55,10.225 31.55,10.425 31.915,10.79 32.39,10.79 ; R8.1@32.275,11.875 33.65,11.875 33.615,11.84 C10.2@33.615,10.79 ; U5.16@32.525,8.65 33.225,8.65 33.625,9.05 33.625,10.78 C10.2@33.615,10.79 ; U5.18@32.525,9.675 32.525,10.45 ; 32.39,10.79 32.865,10.79 ; 32.39,10.79 32.525,10.655 32.525,10.45 ; 32.525,10.45 32.865,10.79 ; 32.865,10.79 C10.2@33.615,10.79
  Bottom Layer w0.25: v1(33.7,14.8) 33.767,14.733 33.977,14.733 34.01,14.7 46.45,14.7 51.3,19.55 51.3,25.438 50.317,26.421 49.715,26.421 JP1.2@49.409,26.727
pads on no net: 1.1 CN1.8 CN1.9 CN3.0 CN3.1 CN3.2 CN3.8 CN3.9 CN3.10 Designator1.1 Designator2.1 U2.9 U2.10 U6.7 U8.3 U8.5

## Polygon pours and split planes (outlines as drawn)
GND on Top Layer "GND_L01_P000" (solid, remove dead copper, pour order 0): -1.47,29.572 -1.47,-0.928 58.605,-0.928 59.33,-0.203 59.33,28.847 58.605,29.572
GND on Bottom Layer "GND_L02_P001" (solid, remove dead copper, pour order 1): 0.225,31.025 -0.75,30.05 -0.75,0.55 0.75,-0.95 58.875,-0.95 60.725,0.9 60.725,29.775 59.475,31.025

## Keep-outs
Keep-Out Layer:
  region: 58.4,25.1 59.55,23.95 59.55,29.55 58.4,28.4
  region: 1.15,25.1 0,23.95 0,29.55 1.15,28.4
  region: 1.15,1.6 0,0.45 0,6.05 1.15,4.9
  region: 58.4,1.6 59.55,0.45 59.55,6.05 58.4,4.9

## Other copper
Top Layer:
  pour cut-out: 33.226,20.348 32.884,20.007 32.884,17.613 33.146,17.352 36.024,17.352 36.337,17.716 36.337,19.082 36.331,19.708 36.331,19.988 36.306,20.014 36.276,20.043 36.201,20.119 36.133,20.215 36.106,20.279 36.095,20.313 36.087,20.348
  text "1" at 2.25,27 h2
Bottom Layer:
  pour cut-out: 36.124,20.222 36.088,20.337 33.218,20.341 32.884,20.007 32.884,17.613 33.146,17.352 36.024,17.352 36.333,17.712 36.333,18.348 36.327,18.673 36.337,18.843 36.333,18.983 36.333,19.103 36.327,19.468 36.333,19.981 36.274,20.041 36.188,20.134
  text "2" at 4.5,27 h2
Multi-Layer:
  pour cut-out: 31.75,0.2 31.75,3.2 27.75,3.2 27.75,0.2
  pour cut-out: 2,28.5 2,26.75 4.75,26.75 4.75,28.5

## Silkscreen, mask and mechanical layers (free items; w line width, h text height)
Top Overlay:
  lines w0.1: 26.144,5.073 26.144,5.732 ; 40.084,24.293 40.606,24.293 ; 46.396,28.025 46.396,28.685
  lines w0.12: 24.721,5.016 24.721,4.485 24.997,4.21 ; 25.64,1.938 25.64,2.176 25.755,2.291 ; 33.902,3.765 34.424,3.765
  lines w0.2: 35.807,1 58.74,1 58.74,6.375 35.807,6.375 35.807,1
  text "Flash_Done" at 43.9,29 h1
  text "GND" at 30.611,28.334 h1.3
  text "GND" at 34.288,28.334 h1.3
  text "Reset" at 41.3,28.178 h1
  text "User" at 12.062,28.08 h1
  text "DEBUG" at 20.65,27.412 h1
  text "E3V3" at 30.55,21.816 h1.3
  text "E5V" at 34.417,21.798 h1.3
  text "IDD" at 48.35,21.65 h1.5
  text "5V_PWR" at 38.05,19.527 h1
  text "STMod+" at 5.534,12.15 h1.3 r90
  text "MB1868E" at 39.089,8.675 h2
  text "J" at 10.9,1.442 h15
Bottom Overlay:
  lines w0.12: 0.32,4.7 1.345,4.7 ; 0.43,25.025 1.455,25.025 ; 7.725,17.604 10.977,17.604 11.187,17.394 ; 7.735,19.4 10.878,19.4 11.097,19.618
  lines w0.2: 26.512,1.796 26.512,10.796 51.512,10.796 51.512,1.796 26.512,1.796
  text "F" at 18.1,22.858 h10
  text "G" at 46.31,22.636 h10
  text "S" at 28,21.9 h10
  text "E" at 50.845,12.39 h8
  text "C" at 32.284,12.379 h8
  text "H" at 42.162,11.969 h10
  text "I" at 55.1,6.75 h8
  text "I" at 19.15,3.75 h8
Top Solder:
  rectangle: 2,26.75 4.75,28.5
Bottom Solder:
  rectangle: 2,26.75 4.75,28.5
M1-Board Shape:
  circle w0.1: c56,26.9 r1.208
  circle w0.1: c6.5,2.65 r1.208
  lines w0.1: 0,1 ccw(c1,1) 1,0 58.55,0 ccw(c58.55,1) 59.55,1 59.55,29 ccw(c58.55,29) 58.55,30 0.902,30 ccw(c0.902,29.124) 0.025,29.124 0,1 ; 32.134,17.65 ccw(c32.509,17.65) 32.884,17.65 32.884,19.995 33.024,20.135 ccw(c32.759,20.4) 32.494,20.665 32.134,20.305 32.134,17.65 ; 36.244,20.157 cw(c36.509,20.422) 36.774,20.687 37.134,20.328 37.134,17.672 cw(c36.759,17.672) 36.384,17.672 36.384,20.017 36.244,20.157
M2-Board Dimensions:
  circle w0.1: c6.5,2.65 r1.197
  circle w0.1: c56,26.9 r1.197
  lines w0.1: 0,29.124 0,1 ccw(c1,1) 1,0 58.55,0 ccw(c58.55,1) 59.55,1 59.55,29 ccw(c58.55,29) 58.55,30 0.902,30 ccw(c0.902,29.124) 0.025,29.124 ; 32.134,17.65 ccw(c32.509,17.65) 32.884,17.65 32.884,19.995 33.024,20.135 ccw(c32.759,20.4) 32.494,20.665 32.134,20.305 32.134,17.65 ; 36.244,20.157 cw(c36.509,20.422) 36.774,20.687 37.134,20.328 37.134,17.672 cw(c36.759,17.672) 36.384,17.672 36.384,20.017 36.244,20.157
M14-Top Assembly:
  text "C9" at 33.653,9.91 h0.75
Drill Drawing:
  drawing of 281 lines, arcs and shapes, not listed
  text "THE COMPONENTS WITH PLATED THROUGH HOLE (PTH) MAY BE WELDED (CABLED) IN \"PIN-IN-PASTE\" MODE (IF NECESSARY) / \"\"TOP PASTE\"\"" at -50.725,104.8 h3
  text "MINIMUM PARAMETERS" at -5.35,99.85 h3
  text "PCB : TYPE 2" at 37.973,99.547 h3
  text "DEFAULT" at -9.482,94.098 h3
  text "ASPECT-RATIO, AXE Z :" at 37.973,94.047 h3
  text "TRACKS : 0.20mm           / GAPS : 0.15mm" at -9.482,88.348 h3
  text "< 6:1 / LEVEL \"A\"" at 37.991,87.299 h3
  text "PCB SPECIFICATIONS :" at -37.589,80.454 h3
  text "A.   MATERIAL :" at -37.589,76.454 h3
  text "FR-4" at 0.911,76.454 h3
  text "TG-170" at 17.411,76.454 h3
  text "TG-150" at 35.661,76.454 h3
  text "X  TG-140" at 51.661,76.454 h3
  text "B.   MATERIAL FAMILY :" at -37.589,73.454 h3
  text "N/A" at 0.911,73.454 h3
  text "C.   SOLDERMASK COLOR :" at -37.589,70.454 h3
  text "GREEN" at 0.911,70.454 h3
  text "WHITE" at 17.411,70.454 h3
  text "RED" at 35.661,70.454 h3
  text "X  Blue ink PANTONE 2955" at 51.661,70.454 h3
  text "D.   SILKSCREEN COLOR :" at -37.589,67.454 h3
  text "X  WHITE" at 0.911,67.454 h3
  text "YELLOW" at 17.411,67.454 h3
  text "BLACK" at 35.661,67.454 h3
  text "Blue ink PANTONE 2955" at 51.661,67.454 h3
  text "E.   SURFACE FINISH :" at -37.589,64.454 h3
  text "X  ENIG" at 0.911,64.454 h3
  text "IMMERSION SILVER" at 17.411,64.454 h3
  text "IMMERSION TIN" at 51.661,64.454 h3
  text "HASL" at 0.911,61.454 h3
  text "HASL (PB-FREE)" at 17.411,61.454 h3
  text "GOLDEN FINGER" at 51.661,61.454 h3
  text "F.   IMPEDANCE CONTROL :" at -37.589,58.454 h3
  text "NO" at 0.911,58.454 h3
  text "YES  (SEE IMPEDANCE TABLE FOR DETAIL INFORMATION)" at 17.411,58.454 h3
  text "G.   THROUGH VIA :" at -37.589,55.454 h3
  text "PLUG THE VIAS WHICH ARE COVERED WITH SOLDERMASK ONE OR TWO SIDE." at 0.911,55.454 h3
  text "PLUG MATERIAL :" at 0.911,52.454 h3
  text "X  SOLDERMASK" at 26.411,52.454 h3
  text "NON-CONDUCTIVE EPOXY." at 51.661,52.454 h3
  text "H.   STACK-UP :" at -37.589,49.454 h3
  text "SEE LAYER STACK-UP SEQUENCE FOR OVERALL THICKNESS." at 0.911,49.454 h3
  text "Layer" at 92.755,24.609 h1.52
  text "Name" at 99.133,24.609 h1.52
  text "Material" at 111.467,24.609 h1.52
  text "Thickness" at 122.55,24.609 h1.52
  text "Constant" at 131.654,24.609 h1.52
  text "Board Layer Stack" at 140.08,24.609 h1.52
  text "Top Overlay" at 99.133,21.561 h1.52
  text "Top Solder" at 99.133,18.513 h1.52
  text "Solder Resist" at 111.467,18.513 h1.52
  text "0.020mm" at 122.55,18.513 h1.52
  text "4.2" at 131.654,18.513 h1.52
  text "1" at 92.755,15.465 h1.52
  text "Top Layer" at 99.133,15.465 h1.52
  text "0.018mm" at 122.55,15.465 h1.52
  text "Dielectric 2" at 99.133,12.417 h1.52
  text "FR-4" at 111.467,12.417 h1.52
  text "1.464mm" at 122.55,12.417 h1.52
  text "4.2" at 131.654,12.417 h1.52
  text "2" at 92.754,9.369 h1.52
  text "Bottom Layer" at 99.133,9.369 h1.52
  text "0.018mm" at 122.55,9.369 h1.52
  text "Bottom Solder" at 99.133,6.321 h1.52
  text "Solder Resist" at 111.467,6.321 h1.52
  text "0.020mm" at 122.55,6.321 h1.52
  text "4.2" at 131.654,6.321 h1.52
  text "Bottom Overlay" at 99.133,3.273 h1.52
  text "Symbol" at -33.863,-35.348 h3
  text "Count" at -22.111,-35.348 h3
  text "Hole Size" at -9.92,-35.348 h3
  text "Plated" at 12.947,-35.348 h3
  text "Hole Type" at 23.264,-35.348 h3
  text "Drill Layer Pair" at 38.283,-35.348 h3
  text "Via/Pad" at 66.75,-35.348 h3
  text "Pad Shape" at 79.057,-35.348 h3
  text "2" at -22.111,-40.525 h2.5
  text "0.970mm (38.19mil)" at -9.92,-40.525 h2.5
  text "NPTH" at 12.947,-40.525 h2.5
  text "Round" at 23.264,-40.525 h2.5
  text "Top Layer - Bottom Layer" at 38.283,-40.525 h2.5
  text "Pad" at 66.75,-40.525 h2.5
  text "Rounded" at 79.057,-40.525 h2.5
  text "2" at -22.111,-45.703 h2.5
  text "2.500mm (98.43mil)" at -9.92,-45.703 h2.5
  text "NPTH" at 12.947,-45.703 h2.5
  text "Slot" at 23.264,-45.703 h2.5
  text "Top Layer - Bottom Layer" at 38.283,-45.703 h2.5
  text "Pad" at 66.75,-45.703 h2.5
  text "Rounded" at 79.057,-45.703 h2.5
  text "4" at -22.111,-50.88 h2.5
  text "0.300mm (11.81mil)" at -9.92,-50.88 h2.5
  text "PTH" at 12.947,-50.88 h2.5
  text "Round" at 23.264,-50.88 h2.5
  text "Top Layer - Bottom Layer" at 38.283,-50.88 h2.5
  text "Via" at 66.75,-50.88 h2.5
  text "Rounded" at 79.057,-50.88 h2.5
  text "6" at -22.111,-56.058 h2.5
  text "1.000mm (39.37mil)" at -9.92,-56.058 h2.5
  text "PTH" at 12.947,-56.058 h2.5
  text "Round" at 23.264,-56.058 h2.5
  text "Top Layer - Bottom Layer" at 38.283,-56.058 h2.5
  text "Pad" at 66.75,-56.058 h2.5
  text "Rounded" at 79.057,-56.058 h2.5
  text "20" at -22.111,-61.235 h2.5
  text "0.900mm (35.43mil)" at -9.92,-61.235 h2.5
  text "PTH" at 12.947,-61.235 h2.5
  text "Round" at 23.264,-61.235 h2.5
  text "Top Layer - Bottom Layer" at 38.283,-61.235 h2.5
  text "Pad" at 66.75,-61.235 h2.5
  text "(Mixed)" at 79.057,-61.235 h2.5
  text "550" at -22.111,-66.413 h2.5
  text "0.300mm (11.81mil)" at -9.92,-66.413 h2.5
  text "PTH" at 12.947,-66.413 h2.5
  text "Round" at 23.264,-66.413 h2.5
  text "Top Layer - Bottom Layer" at 38.283,-66.413 h2.5
  text "Via" at 66.75,-66.413 h2.5
  text "Rounded" at 79.057,-66.413 h2.5
  text "584 Total" at -22.111,-71.59 h2.5
  text "Slot definitions :" at -33.863,-75.214 h2.5
  text "Routed Path Length" at -16.801,-75.214 h2.5
  text "= Calculated from tool start centre position to tool end centre position." at 4.335,-75.214 h2.5
  text "Hole Length" at -16.801,-77.285 h2.5
  text "= Routed Path Length + Tool Size = Slot length as defined in the PCB layout" at -3.512,-77.285 h2.5

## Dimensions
5.23,2.535 to 7.727,2.785 on M2-Board Dimensions
54.803,26.9 to 58.55,30 on M2-Board Dimensions
58.55,0 to 56.3,15 on M2-Board Dimensions
-4.9,4.675 to 1,0 on M2-Board Dimensions
0.902,30 to -4.9,25.325 on M2-Board Dimensions
6.5,2.65 to 1,0 on M2-Board Dimensions
0,1 to 6.5,2.65 on M2-Board Dimensions
0,1 to 55.977,26.903 on M2-Board Dimensions
54.7,26.65 to 57.197,26.9 on M2-Board Dimensions
0,29.124 to 59.55,29 on M2-Board Dimensions
0.902,30 to 1,0 on M2-Board Dimensions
